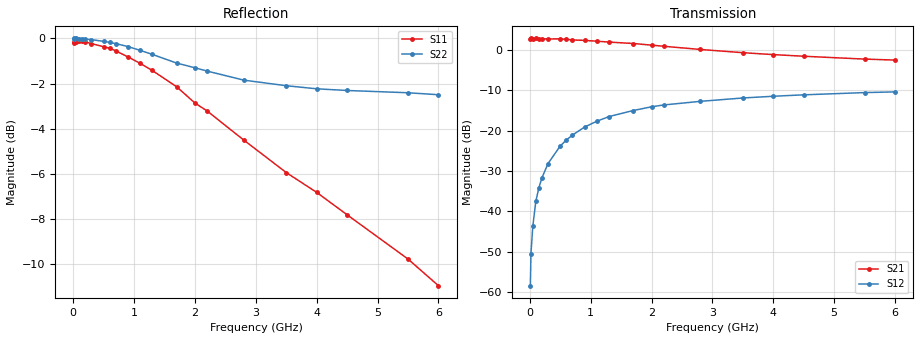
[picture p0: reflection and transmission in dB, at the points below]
! SIEMENS Discrete & RF Semiconductors
! BFY180
! Si NPN RF Bipolar Junction Transistor in MICRO-X
! VCE = 0.5 V  IC = 0.4 mA
! Common Emitter S-Parameters:  May  1997
# GHz  S  MA  R  50
!  f  S11  S21  S12  S22
! GHz  MAG  ANG  MAG  ANG  MAG  ANG  MAG  ANG
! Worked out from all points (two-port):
!   36 points, 10 MHz to 6 GHz, reference 50 ohm
!   highest |S21| = 2.84 dB at 100 MHz (marker M1); lowest = -2.5 dB at 6 GHz (marker M2)
!   |S21| within 3 dB of the highest: start of sweep to 2.971 GHz
!   lowest |S11| = -10.9 dB at 6 GHz (marker M3), VSWR 1.79, Z = 30.1 - j11.3 ohm
!   |S11| at or under -10 dB: 5.6 GHz to end of sweep
!   |S22| runs from -2.5 to 0.0 dB; largest |S21 - S12| = 1.4
!   S11 on the Smith chart (normalised r, x): 10 MHz: open; 700 MHz: 0.68, -4.47; 1.3 GHz: 0.55, -2.34; 2.2 GHz: 0.52, -1.30; 4 GHz: 0.55, -0.61; 6 GHz: 0.60, -0.23
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0.01  0.9824 -0.2  1.371 179.9  0.0012 79.9  0.9978 -0.2
0.02  0.9774 -0.7  1.382 179.2  0.003 86.1  0.9999 -0.5
0.05  0.9814 -1.6  1.364 177.9  0.0065 89.7  0.9997 -1.3
0.1  0.9869 -3.6  1.387 175.6  0.0133 87.4  0.9977 -2.6
0.15  0.9843 -5.5  1.366 173.3  0.0196 85.1  0.9979 -3.8
0.2  0.9818 -7.1  1.367 170.6  0.026 84.5  0.9967 -5.1
0.3  0.9737 -10.6  1.365 165.9  0.039 81.3  0.9933 -7.7
0.5  0.9584 -18.0  1.366 156.4  0.0644 75.5  0.985 -12.6
0.6  0.9509 -21.2  1.35 151.4  0.0762 72.6  0.9796 -15.0
0.7  0.9384 -24.7  1.326 147.9  0.0878 69.5  0.9738 -17.5
0.9  0.9101 -31.4  1.309 138.9  0.1105 64.2  0.959 -22.3
1.1  0.8805 -37.8  1.28 130.4  0.1305 59.0  0.9408 -26.8
1.3  0.8491 -44.5  1.248 122.4  0.1489 53.7  0.9216 -31.3
1.7  0.7816 -56.6  1.198 106.9  0.1773 45.0  0.8817 -39.3
2  0.7194 -64.5  1.143 95.1  0.1971 39.3  0.8608 -44.7
2.2  0.691 -69.6  1.107 88.6  0.2076 35.4  0.8466 -48.3
2.8  0.596 -83.2  1.011 70.4  0.2302 26.5  0.8083 -57.4
3.5  0.5048 -96.2  0.922 52.1  0.2534 17.9  0.7856 -67.2
4  0.4563 -104.9  0.873 40.4  0.2662 12.0  0.7733 -74.2
4.5  0.407 -113.5  0.833 29.9  0.2772 6.5  0.7667 -81.3
5.5  0.3249 -131.4  0.768 10.8  0.2955 -4.2  0.7579 -95.5
6  0.2836 -142.4  0.747 2.2  0.3015 -9.5  0.7503 -102.6
